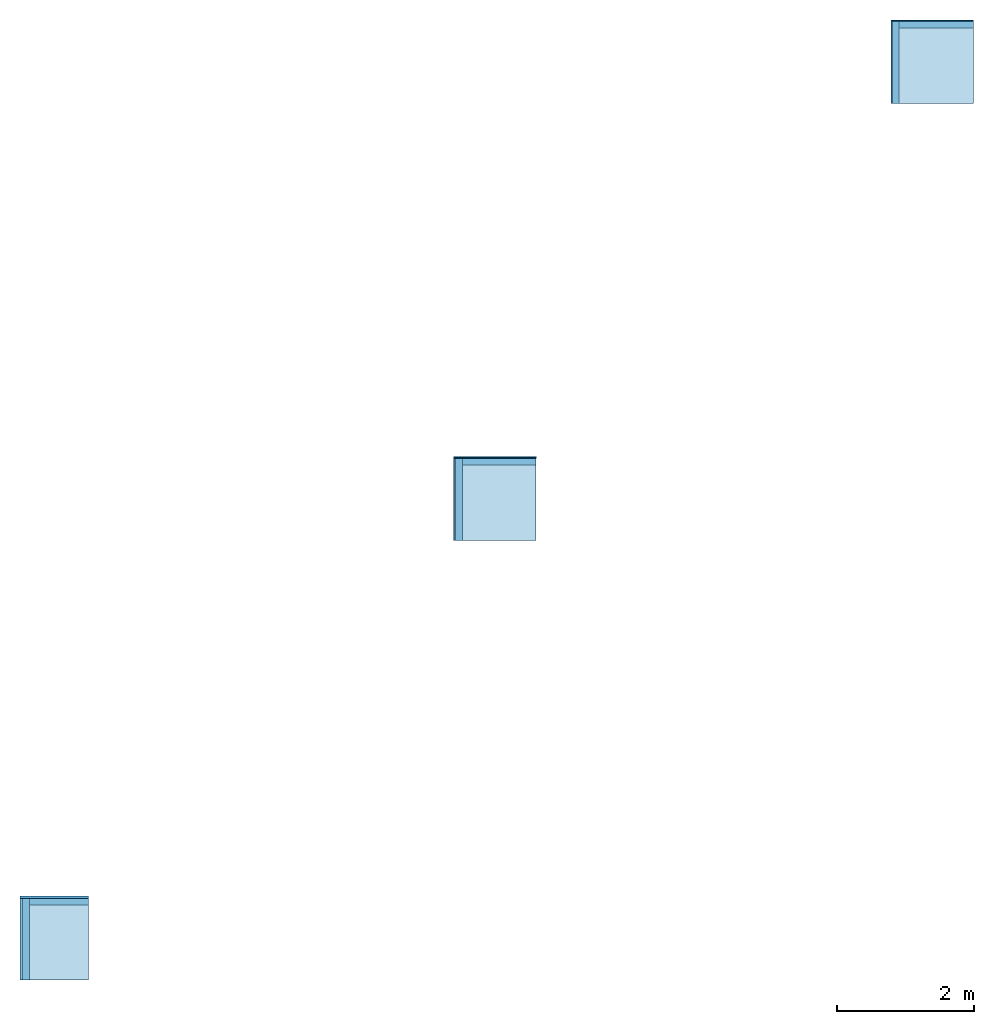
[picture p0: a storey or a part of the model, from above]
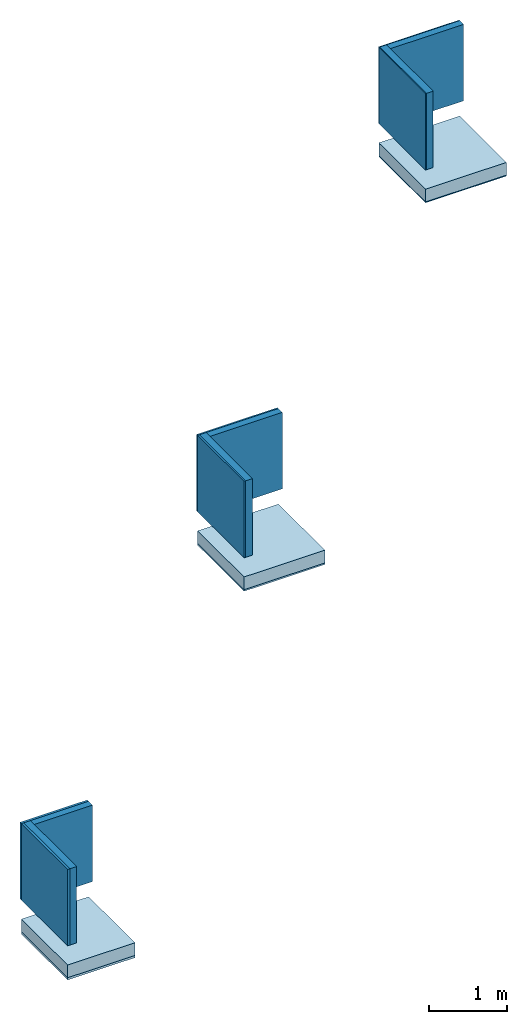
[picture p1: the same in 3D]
Properties of the parts of a building model (IFC2X3)

# File
Description: ViewDefinition [CoordinationView, QuantityTakeOffAddOnView]
File name: 012345
Time: 2023-01-18T09:38:41
Written by: The EXPRESS Data Manager Version 5.02.0100.07 : 28 Aug 2013
Made in: 21.1.70.21 - Exporter 21.1.70.21 - Alternate UI 21.1.70.21
Comment: STEP Physical File produced by: The EXPRESS Data Manager Version 5.02.0100.07 : 28 Aug 2013 * Module: EDMstepFileFactory/EDMstandAlone * Creation date: Wed Jan 18 09:38:41 2023 * Host: BIM-LT03 * Database: C:\Users\DONNEE~1\AppData\Local\Temp\6dfd9f73-01cb-4fe2-bb7c-203e315a706e\4447c928-8483-4c6d-8fab-7a3299bfe652\ifc * Database version: 5507 * Database creation date: Wed Jan 18 09:38:40 2023 * Schema: IFC2X3 * Model: DataRepository.ifc * Model creation date: Wed Jan 18 09:38:41 2023 * Header model: DataRepository.ifc_HeaderModel * Header model creation date: Wed Jan 18 09:38:41 2023 * EDMuser: sdai-user * EDMgroup: sdai-group * License ID and type: 5605 : Permanent license. Expiry date: * EDMstepFileFactory options: 020000

# IfcProject, 012345
LongName: Cadix Project Naam; Phase: Cadix leeg V2.0

# IfcSite, Default
RefLatitude: 52, 3, 20, 225830; RefLongitude: 5, 6, 28, 692855; RefElevation: 0 mm
Pset_ProductRequirements - Category: Project Information

# IfcBuilding
Pset_BuildingCommon - NumberOfStoreys: 2
Pset_ProductRequirements - Category: Project Information

# IfcBuildingStorey: Level:niveau (2)
Pset_ProductRequirements - Category: Levels
Name | LongName = Pset_AirSideSystemInformation, Name = Pset_ProductRequirements, Name | Elevation (mm)
00 begane grond | 00 begane grond | -2.7707e-11
01 eerste verdieping | 01 eerste verdieping | 1200

# IfcCovering: Compound Ceiling:NLRS_45_CEI_Heraklith A2 afbouwpaneel 15x1200x600mm, Compound Ceiling:NLRS_45_CEI_Heraklith A2 afbouwpaneel 15x1200x600mm:888459
In: 01 eerste verdieping
Type - PredefinedType: CEILING
Type - Pset_CoveringCommon - Reference: Compound Ceiling:NLRS_45_CEI_Heraklith A2 afbouwpaneel 15x1200x600mm; TotalThickness: 15 mm
Type - Pset_ElementShading - Roughness: 304.8 mm
Type - Pset_ManufacturerTypeInformation - Manufacturer: Knauf Insulation B.V.
Type - Pset_ProductRequirements - Category: Ceilings
Type - Pset_QuantityTakeOff - Reference: Compound Ceiling:NLRS_45_CEI_Heraklith A2 afbouwpaneel 15x1200x600mm
Type - Pset_Ceiling_Schedule_LOD200 - Assembly Code: 45.0; Type Image: Raster image: Heraklith A2 Afbouwpaneel.jpg; Model: Heraklith® | A2 afbouwpaneel is een A2 houtwolcementpaneel; Manufacturer: Knauf Insulation B.V.; URL: www.heraklith.nl; Description: A2 afbouwpaneel - 15mm; phone: +31(0)162-421245; email: customerservice.nl@knaufinsulation.com; product URL: https://heraklith.nl/houtwol-producten/a2-afbouwpaneel; warmteweerstand: 0,15 (m2.K/W); NLRS_C_Code_Brandklasse: A2-s1,d0; brandweerstand: REI 60 mits verwerkt tegen massief beton conform classificatierapport nr 16210B / 16211B; geluidsabsorbtie: niet getest; DoP: W4302APCPR; NLRS_C_content_creator: Knauf Insulation; NLRS_C_content_versie: V1.0
Classification: 45.0 (Uniformat); Material: Heraklith A2 afbouwpaneel - Houtwollaag - 1200x600mm 15 mm
Pset_CoveringCommon - Finish: Heraklith A2 afbouwpaneel - Houtwollaag - 1200x600mm;
Pset_Ceiling_Schedule_LOD200 - Type: Compound Ceiling: NLRS_45_CEI_Heraklith A2 afbouwpaneel 15x1200x600mm
BaseQuantities - GrossCeilingArea: 1.44 m2

# IfcCovering: Compound Ceiling:NLRS_45_CEI_Heraklith A2 afbouwpaneel 25x1200x600mm, Compound Ceiling:NLRS_45_CEI_Heraklith A2 afbouwpaneel 25x1200x600mm:912503
In: 01 eerste verdieping
Type - PredefinedType: CEILING
Type - Pset_CoveringCommon - Reference: Compound Ceiling:NLRS_45_CEI_Heraklith A2 afbouwpaneel 25x1200x600mm; TotalThickness: 25 mm
Type - Pset_ElementShading - Roughness: 304.8 mm
Type - Pset_ManufacturerTypeInformation - Manufacturer: Knauf Insulation B.V.
Type - Pset_ProductRequirements - Category: Ceilings
Type - Pset_QuantityTakeOff - Reference: Compound Ceiling:NLRS_45_CEI_Heraklith A2 afbouwpaneel 25x1200x600mm
Type - Pset_Ceiling_Schedule_LOD200 - Assembly Code: 45.0; Type Image: Raster image: Heraklith A2 Afbouwpaneel.jpg; Model: Heraklith® | A2 afbouwpaneel is een A2 houtwolcementpaneel; Manufacturer: Knauf Insulation B.V.; URL: www.heraklith.nl; Description: A2 afbouwpaneel - 25mm; phone: +31(0)162-421245; email: customerservice.nl@knaufinsulation.com; product URL: https://heraklith.nl/houtwol-producten/a2-afbouwpaneel; warmteweerstand: 0,25 (m2.K/W); NLRS_C_Code_Brandklasse: A2-s1,d0; brandweerstand: REI 60 mits verwerkt tegen massief beton conform classificatierapport nr 16210B / 16211B; geluidsabsorbtie: max. 0,90; DoP: W4302APCPR; NLRS_C_content_creator: Knauf Insulation; NLRS_C_content_versie: V1.0
Classification: 45.0 (Uniformat); Material: Heraklith A2 afbouwpaneel - Houtwollaag - 1200x600mm 25 mm
Pset_CoveringCommon - Finish: Heraklith A2 afbouwpaneel - Houtwollaag - 1200x600mm;
Pset_Ceiling_Schedule_LOD200 - Type: Compound Ceiling: NLRS_45_CEI_Heraklith A2 afbouwpaneel 25x1200x600mm
BaseQuantities - GrossCeilingArea: 1.434 m2

# IfcCovering: Compound Ceiling:NLRS_45_CEI_Heraklith A2 afbouwpaneel 35x1000x600mm, Compound Ceiling:NLRS_45_CEI_Heraklith A2 afbouwpaneel 35x1000x600mm:914120
In: 01 eerste verdieping
Type - PredefinedType: CEILING
Type - Pset_CoveringCommon - Reference: Compound Ceiling:NLRS_45_CEI_Heraklith A2 afbouwpaneel 35x1000x600mm; TotalThickness: 35 mm
Type - Pset_ElementShading - Roughness: 304.8 mm
Type - Pset_ManufacturerTypeInformation - Manufacturer: Knauf Insulation B.V.
Type - Pset_ProductRequirements - Category: Ceilings
Type - Pset_QuantityTakeOff - Reference: Compound Ceiling:NLRS_45_CEI_Heraklith A2 afbouwpaneel 35x1000x600mm
Type - Pset_Ceiling_Schedule_LOD200 - Assembly Code: 45.0; Type Image: Raster image: Heraklith A2 Afbouwpaneel.jpg; Model: Heraklith® | A2 afbouwpaneel is een A2 houtwolcementpaneel; Manufacturer: Knauf Insulation B.V.; URL: www.heraklith.nl; Description: A2 afbouwpaneel - 35mm; phone: +31(0)162-421245; email: customerservice.nl@knaufinsulation.com; product URL: https://heraklith.nl/houtwol-producten/a2-afbouwpaneel; warmteweerstand: 0,40 (m2.K/W); NLRS_C_Code_Brandklasse: A2-s1,d0; brandweerstand: REI 60 mits verwerkt tegen massief beton conform classificatierapport nr 16210B / 16211B; geluidsabsorbtie: 0,40; DoP: W4302APCPR; NLRS_C_content_creator: Knauf Insulation; NLRS_C_content_versie: V1.0
Classification: 45.0 (Uniformat); Material: Heraklith A2 afbouwpaneel - Houtwollaag - 1000x600mm 35 mm
Pset_CoveringCommon - Finish: Heraklith A2 afbouwpaneel - Houtwollaag - 1000x600mm;
Pset_Ceiling_Schedule_LOD200 - Type: Compound Ceiling: NLRS_45_CEI_Heraklith A2 afbouwpaneel 35x1000x600mm
BaseQuantities - GrossCeilingArea: 1.19 m2

# IfcSlab: Floor:Generic 200mm (6)
Type - PredefinedType: FLOOR; Material: Concrete, Precast Panels 200 mm
Type - Pset_ElementShading - Roughness: 914.4 mm
Type - Pset_ProductRequirements - Category: Floors
Type - Pset_QuantityTakeOff - Reference: Floor:Generic 200mm
Type - Pset_ReinforcementBarPitchOfSlab - Reference: Floor:Generic 200mm
Type - Pset_SlabCommon - IsExternal: no; Reference: Floor:Generic 200mm; ThermalTransmittance: 5.23 kg/K/s3
Pset_QuantityTakeOff - sets with these values: 2
Pset_SlabCommon - LoadBearing: no; PitchAngle: 0 deg
BaseQuantities - Width: 200 mm
Name (Floor:Generic 200mm:...) | In | GrossArea (m2) | NetArea (m2) | GrossVolume (m3) | NetVolume (m3) | Perimeter (mm)
915309 | 00 begane grond | 1.44 | 3.84 | 288 | 0.288 | 4800
915454 | 00 begane grond | 1.434 | 3.826 | 286.8 | 0.2868 | 4790
915523 | 00 begane grond | 1.19 | 3.256 | 238 | 0.238 | 4380
916757 | 01 eerste verdieping | 1.44 | 3.84 | 288 | 0.288 | 4800
916812 | 01 eerste verdieping | 1.434 | 3.826 | 286.8 | 0.2868 | 4790
916986 | 01 eerste verdieping | 1.19 | 3.256 | 238 | 0.238 | 4380

# IfcSlab: Floor:NLRS_23_FL_Heraklith A2 afbouwpaneel 15x1200x600mm, Floor:NLRS_23_FL_Heraklith A2 afbouwpaneel 15x1200x600mm:889765
In: 00 begane grond
Type - PredefinedType: FLOOR; Material: Heraklith A2 afbouwpaneel - Houtwollaag - 1200x600mm 15 mm
Type - Pset_ElementShading - Roughness: 304.8 mm
Type - Pset_ManufacturerTypeInformation - Manufacturer: Knauf Insulation B.V.
Type - Pset_ProductRequirements - Category: Floors
Type - Pset_QuantityTakeOff - Reference: Floor:NLRS_23_FL_Heraklith A2 afbouwpaneel 15x1200x600mm
Type - Pset_ReinforcementBarPitchOfSlab - Description: A2 afbouwpaneel - 15mm; Reference: Floor:NLRS_23_FL_Heraklith A2 afbouwpaneel 15x1200x600mm
Type - Pset_SlabCommon - IsExternal: no; Reference: Floor:NLRS_23_FL_Heraklith A2 afbouwpaneel 15x1200x600mm; ThermalTransmittance: 56.6667 kg/K/s3
Type - Pset_Floor_Schedule_ LOD200 - Assembly Code: 23.0; Type Image: Raster image: Heraklith A2 Afbouwpaneel.jpg; Model: Heraklith® | A2 afbouwpaneel is een A2 houtwolcementpaneel; Manufacturer: Knauf Insulation B.V.; URL: www.heraklith.nl; Description: A2 afbouwpaneel - 15mm; phone: +31(0)162-421245; email: customerservice.nl@knaufinsulation.com; product URL: https://heraklith.nl/houtwol-producten/a2-afbouwpaneel; warmteweerstand: 0,15 (m2.K/W); NLRS_C_Code_Brandklasse: A2-s1,d0; brandweerstand: REI 60 mits verwerkt tegen massief beton conform classificatierapport nr 16210B / 16211B; geluidsabsorbtie: niet getest; DoP: W4302APCPR; NLRS_C_content_creator: Knauf Insulation; NLRS_C_content_versie: V1.0
Classification: 23.0 (Uniformat)
Pset_SlabCommon - LoadBearing: no; IsExternal: yes; PitchAngle: 0 deg
Pset_Floor_Schedule_ LOD200 - Type: Floor: NLRS_23_FL_Heraklith A2 afbouwpaneel 15x1200x600mm
BaseQuantities - GrossArea: 1.44 m2; NetArea: 2.952 m2; GrossVolume: 21.6 m3; NetVolume: 0.0216 m3; Perimeter: 4800 mm; Width: 15 mm

# IfcSlab: Floor:NLRS_23_FL_Heraklith A2 afbouwpaneel 25x1200x600mm, Floor:NLRS_23_FL_Heraklith A2 afbouwpaneel 25x1200x600mm:912512
In: 00 begane grond
Type - PredefinedType: FLOOR; Material: Heraklith A2 afbouwpaneel - Houtwollaag - 1200x600mm 25 mm
Type - Pset_ElementShading - Roughness: 304.8 mm
Type - Pset_ManufacturerTypeInformation - Manufacturer: Knauf Insulation B.V.
Type - Pset_ProductRequirements - Category: Floors
Type - Pset_QuantityTakeOff - Reference: Floor:NLRS_23_FL_Heraklith A2 afbouwpaneel 25x1200x600mm
Type - Pset_ReinforcementBarPitchOfSlab - Description: A2 afbouwpaneel - 25mm; Reference: Floor:NLRS_23_FL_Heraklith A2 afbouwpaneel 25x1200x600mm
Type - Pset_SlabCommon - IsExternal: no; Reference: Floor:NLRS_23_FL_Heraklith A2 afbouwpaneel 25x1200x600mm; ThermalTransmittance: 34 kg/K/s3
Type - Pset_Floor_Schedule_ LOD200 - Assembly Code: 23.0; Type Image: Raster image: Heraklith A2 Afbouwpaneel.jpg; Model: Heraklith® | A2 afbouwpaneel is een A2 houtwolcementpaneel; Manufacturer: Knauf Insulation B.V.; URL: www.heraklith.nl; Description: A2 afbouwpaneel - 25mm; phone: +31(0)162-421245; email: customerservice.nl@knaufinsulation.com; product URL: https://heraklith.nl/houtwol-producten/a2-afbouwpaneel; warmteweerstand: 0,25 (m2.K/W); NLRS_C_Code_Brandklasse: A2-s1,d0; brandweerstand: REI 60 mits verwerkt tegen massief beton conform classificatierapport nr 16210B / 16211B; geluidsabsorbtie: max. 0,90; DoP: W4302APCPR; NLRS_C_content_creator: Knauf Insulation; NLRS_C_content_versie: V1.0
Classification: 23.0 (Uniformat)
Pset_SlabCommon - LoadBearing: no; IsExternal: yes; PitchAngle: 0 deg
Pset_Floor_Schedule_ LOD200 - Type: Floor: NLRS_23_FL_Heraklith A2 afbouwpaneel 25x1200x600mm
BaseQuantities - GrossArea: 1.434 m2; NetArea: 2.98775 m2; GrossVolume: 35.85 m3; NetVolume: 0.03585 m3; Perimeter: 4790 mm; Width: 25 mm

# IfcSlab: Floor:NLRS_23_FL_Heraklith A2 afbouwpaneel 35x1000x600mm, Floor:NLRS_23_FL_Heraklith A2 afbouwpaneel 35x1000x600mm:914109
In: 00 begane grond
Type - PredefinedType: FLOOR; Material: Heraklith A2 afbouwpaneel - Houtwollaag - 1000x600mm 35 mm
Type - Pset_ElementShading - Roughness: 304.8 mm
Type - Pset_ManufacturerTypeInformation - Manufacturer: Knauf Insulation B.V.
Type - Pset_ProductRequirements - Category: Floors
Type - Pset_QuantityTakeOff - Reference: Floor:NLRS_23_FL_Heraklith A2 afbouwpaneel 35x1000x600mm
Type - Pset_ReinforcementBarPitchOfSlab - Description: A2 afbouwpaneel - 35mm; Reference: Floor:NLRS_23_FL_Heraklith A2 afbouwpaneel 35x1000x600mm
Type - Pset_SlabCommon - IsExternal: no; Reference: Floor:NLRS_23_FL_Heraklith A2 afbouwpaneel 35x1000x600mm; ThermalTransmittance: 24.2857 kg/K/s3
Type - Pset_Floor_Schedule_ LOD200 - Assembly Code: 23.0; Type Image: Raster image: Heraklith A2 Afbouwpaneel.jpg; Model: Heraklith® | A2 afbouwpaneel is een A2 houtwolcementpaneel; Manufacturer: Knauf Insulation B.V.; URL: www.heraklith.nl; Description: A2 afbouwpaneel - 35mm; phone: +31(0)162-421245; email: customerservice.nl@knaufinsulation.com; product URL: https://heraklith.nl/houtwol-producten/a2-afbouwpaneel; warmteweerstand: 0,40 (m2.K/W); NLRS_C_Code_Brandklasse: A2-s1,d0; brandweerstand: REI 60 mits verwerkt tegen massief beton conform classificatierapport nr 16210B / 16211B; geluidsabsorbtie: 0,40; DoP: W4302APCPR; NLRS_C_content_creator: Knauf Insulation; NLRS_C_content_versie: V1.0
Classification: 23.0 (Uniformat)
Pset_SlabCommon - LoadBearing: no; IsExternal: yes; PitchAngle: 0 deg
Pset_Floor_Schedule_ LOD200 - Type: Floor: NLRS_23_FL_Heraklith A2 afbouwpaneel 35x1000x600mm
BaseQuantities - GrossArea: 1.19 m2; NetArea: 2.5333 m2; GrossVolume: 41.65 m3; NetVolume: 0.04165 m3; Perimeter: 4380 mm; Width: 35 mm

# IfcWallStandardCase: Basic Wall:Generic_100mm (6)
In: 00 begane grond
Type - PredefinedType: STANDARD; Material: Concrete, Precast Panels 100 mm
Type - Pset_ElementShading - Roughness: 914.4 mm
Type - Pset_ProductRequirements - Category: Walls
Type - Pset_QuantityTakeOff - Reference: Basic Wall:Generic_100mm
Type - Pset_ReinforcementBarPitchOfWall - Reference: Basic Wall:Generic_100mm
Type - Pset_WallCommon - IsExternal: no; Reference: Basic Wall:Generic_100mm; ThermalTransmittance: 10.46 kg/K/s3
BaseQuantities - Height: 1200 mm; Width: 100 mm
Pset_QuantityTakeOff - sets with these values: 2
Pset_WallCommon - ExtendToStructure: no; LoadBearing: no; IsExternal: yes
Name (Basic Wall:Generic_100mm:...) | Length (mm) | GrossFootprintArea (m2) | NetVolume (m3) | NetSideArea (m2)
915746 | 1200 | 0.12 | 144000000 | 1440000
915832 | 1085 | 0.1085 | 130200000 | 1302000
916208 | 1195 | 0.1195 | 143400000 | 1434000
916288 | 1075 | 0.1075 | 129000000 | 1290000
916512 | 1190 | 0.119 | 142800000 | 1428000
916584 | 865 | 0.0865 | 103800000 | 1038000

# IfcWallStandardCase: Basic Wall:NLRS_41_WA_Heraklith A2 afbouwpaneel 15x1200x600mm, Basic Wall:NLRS_41_WA_Heraklith A2 afbouwpaneel 15x1200x600mm:888766
In: 00 begane grond
Type - PredefinedType: STANDARD; Material: Heraklith A2 afbouwpaneel - Houtwollaag - 1200x600mm 15 mm
Type - Pset_ElementShading - Roughness: 304.8 mm
Type - Pset_ManufacturerTypeInformation - Manufacturer: Knauf Insulation B.V.
Type - Pset_ProductRequirements - Category: Walls
Type - Pset_QuantityTakeOff - Reference: Basic Wall:NLRS_41_WA_Heraklith A2 afbouwpaneel 15x1200x600mm
Type - Pset_ReinforcementBarPitchOfWall - Description: A2 afbouwpaneel - 15mm; Reference: Basic Wall:NLRS_41_WA_Heraklith A2 afbouwpaneel 15x1200x600mm
Type - Pset_WallCommon - Reference: Basic Wall:NLRS_41_WA_Heraklith A2 afbouwpaneel 15x1200x600mm; ThermalTransmittance: 56.6667 kg/K/s3; IsExternal: no
Type - Pset_Wall_Schedule_LOD200 - Assembly Code: 41.10; Type Image: Raster image: Heraklith A2 Afbouwpaneel.jpg; Model: Heraklith® | A2 afbouwpaneel is een A2 houtwolcementpaneel; Manufacturer: Knauf Insulation B.V.; URL: www.heraklith.nl; Description: A2 afbouwpaneel - 15mm; phone: +31(0)162-421245; email: customerservice.nl@knaufinsulation.com; product URL: https://heraklith.nl/houtwol-producten/a2-afbouwpaneel; warmteweerstand: 0,15 (m2.K/W); NLRS_C_Code_Brandklasse: A2-s1,d0; brandweerstand: REI 60 mits verwerkt tegen massief beton conform classificatierapport nr 16210B / 16211B; geluidsabsorbtie: niet getest; DoP: W4302APCPR; NLRS_C_content_creator: Knauf Insulation; NLRS_C_content_versie: V1.0
Classification: 41.10 (Uniformat)
BaseQuantities - Height: 1200 mm; Length: 1200 mm; Width: 15 mm; GrossFootprintArea: 0.018 m2; NetVolume: 21600000 m3; NetSideArea: 1440000 m2
Pset_WallCommon - ExtendToStructure: no; LoadBearing: no
Pset_Wall_Schedule_LOD200 - Type: Basic Wall: NLRS_41_WA_Heraklith A2 afbouwpaneel 15x1200x600mm

# IfcWallStandardCase: Basic Wall:NLRS_41_WA_Heraklith A2 afbouwpaneel 25x1200x600mm, Basic Wall:NLRS_41_WA_Heraklith A2 afbouwpaneel 25x1200x600mm:912508
In: 00 begane grond
Type - PredefinedType: STANDARD; Material: Heraklith A2 afbouwpaneel - Houtwollaag - 1200x600mm 25 mm
Type - Pset_ElementShading - Roughness: 304.8 mm
Type - Pset_ManufacturerTypeInformation - Manufacturer: Knauf Insulation B.V.
Type - Pset_ProductRequirements - Category: Walls
Type - Pset_QuantityTakeOff - Reference: Basic Wall:NLRS_41_WA_Heraklith A2 afbouwpaneel 25x1200x600mm
Type - Pset_ReinforcementBarPitchOfWall - Description: A2 afbouwpaneel - 25mm; Reference: Basic Wall:NLRS_41_WA_Heraklith A2 afbouwpaneel 25x1200x600mm
Type - Pset_WallCommon - IsExternal: no; Reference: Basic Wall:NLRS_41_WA_Heraklith A2 afbouwpaneel 25x1200x600mm; ThermalTransmittance: 34 kg/K/s3
Type - Pset_Wall_Schedule_LOD200 - Assembly Code: 41.10; Type Image: Raster image: Heraklith A2 Afbouwpaneel.jpg; Model: Heraklith® | A2 afbouwpaneel is een A2 houtwolcementpaneel; Manufacturer: Knauf Insulation B.V.; URL: www.heraklith.nl; Description: A2 afbouwpaneel - 25mm; phone: +31(0)162-421245; email: customerservice.nl@knaufinsulation.com; product URL: https://heraklith.nl/houtwol-producten/a2-afbouwpaneel; warmteweerstand: 0,25 (m2.K/W) v; NLRS_C_Code_Brandklasse: A2-s1,d0; brandweerstand: REI 60 mits verwerkt tegen massief beton conform classificatierapport nr 16210B / 16211B; geluidsabsorbtie: max. 0,90; DoP: W4302APCPR; NLRS_C_content_creator: Knauf Insulation; NLRS_C_content_versie: V1.0
Classification: 41.10 (Uniformat)
BaseQuantities - Height: 1200 mm; Length: 1200 mm; Width: 25 mm; GrossFootprintArea: 0.03 m2; NetVolume: 36000000 m3; NetSideArea: 1440000 m2
Pset_WallCommon - ExtendToStructure: no; LoadBearing: no; IsExternal: yes
Pset_Wall_Schedule_LOD200 - Type: Basic Wall: NLRS_41_WA_Heraklith A2 afbouwpaneel 25x1200x600mm

# IfcWallStandardCase: Basic Wall:NLRS_41_WA_Heraklith A2 afbouwpaneel 35x1000x600mm, Basic Wall:NLRS_41_WA_Heraklith A2 afbouwpaneel 35x1000x600mm:914281
In: 00 begane grond
Type - PredefinedType: STANDARD; Material: Heraklith A2 afbouwpaneel - Houtwollaag - 1000x600mm 35 mm
Type - Pset_ElementShading - Roughness: 304.8 mm
Type - Pset_ManufacturerTypeInformation - Manufacturer: Knauf Insulation B.V.
Type - Pset_ProductRequirements - Category: Walls
Type - Pset_QuantityTakeOff - Reference: Basic Wall:NLRS_41_WA_Heraklith A2 afbouwpaneel 35x1000x600mm
Type - Pset_ReinforcementBarPitchOfWall - Description: A2 afbouwpaneel - 35mm; Reference: Basic Wall:NLRS_41_WA_Heraklith A2 afbouwpaneel 35x1000x600mm
Type - Pset_WallCommon - IsExternal: no; Reference: Basic Wall:NLRS_41_WA_Heraklith A2 afbouwpaneel 35x1000x600mm; ThermalTransmittance: 24.2857 kg/K/s3
Type - Pset_Wall_Schedule_LOD200 - Assembly Code: 41.10; Type Image: Raster image: Heraklith A2 Afbouwpaneel.jpg; Model: Heraklith® | A2 afbouwpaneel is een A2 houtwolcementpaneel; Manufacturer: Knauf Insulation B.V.; URL: www.heraklith.nl; Description: A2 afbouwpaneel - 35mm; phone: +31(0)162-421245; email: customerservice.nl@knaufinsulation.com; product URL: https://heraklith.nl/houtwol-producten/a2-afbouwpaneel; warmteweerstand: 0,40 (m2.K/W); NLRS_C_Code_Brandklasse: A2-s1,d0; brandweerstand: REI 60 mits verwerkt tegen massief beton conform classificatierapport nr 16210B / 16211B; geluidsabsorbtie: 0,40; DoP: W4302APCPR; NLRS_C_content_creator: Knauf Insulation; NLRS_C_content_versie: V1.0
Classification: 41.10 (Uniformat)
BaseQuantities - Height: 1200 mm; Length: 1000 mm; Width: 35 mm; GrossFootprintArea: 0.035 m2; NetVolume: 42000000 m3; NetSideArea: 1200000 m2
Pset_WallCommon - ExtendToStructure: no; LoadBearing: no; IsExternal: yes
Pset_Wall_Schedule_LOD200 - Type: Basic Wall: NLRS_41_WA_Heraklith A2 afbouwpaneel 35x1000x600mm

# IfcWallStandardCase: Basic Wall:NLRS_42_WA_Heraklith A2 afbouwpaneel 15x1200x600mm, Basic Wall:NLRS_42_WA_Heraklith A2 afbouwpaneel 15x1200x600mm:890945
In: 00 begane grond
Type - PredefinedType: STANDARD; Material: Heraklith A2 afbouwpaneel - Houtwollaag - 1200x600mm 15 mm
Type - Pset_ElementShading - Roughness: 304.8 mm
Type - Pset_ManufacturerTypeInformation - Manufacturer: Knauf Insulation B.V.
Type - Pset_ProductRequirements - Category: Walls
Type - Pset_QuantityTakeOff - Reference: Basic Wall:NLRS_42_WA_Heraklith A2 afbouwpaneel 15x1200x600mm
Type - Pset_ReinforcementBarPitchOfWall - Description: A2 afbouwpaneel - 15mm; Reference: Basic Wall:NLRS_42_WA_Heraklith A2 afbouwpaneel 15x1200x600mm
Type - Pset_WallCommon - IsExternal: no; Reference: Basic Wall:NLRS_42_WA_Heraklith A2 afbouwpaneel 15x1200x600mm; ThermalTransmittance: 56.6667 kg/K/s3
Type - Pset_Wall_Schedule_LOD200 - Assembly Code: 42.10; Type Image: Raster image: Heraklith A2 Afbouwpaneel.jpg; Model: Heraklith® | A2 afbouwpaneel is een A2 houtwolcementpaneel; Manufacturer: Knauf Insulation B.V.; URL: www.heraklith.nl; Description: A2 afbouwpaneel - 15mm; phone: +31(0)162-421245; email: customerservice.nl@knaufinsulation.com; product URL: https://heraklith.nl/houtwol-producten/a2-afbouwpaneel; warmteweerstand: 0,15 (m2.K/W); NLRS_C_Code_Brandklasse: A2-s1,d0; brandweerstand: REI 60 mits verwerkt tegen massief beton conform classificatierapport nr 16210B / 16211B; geluidsabsorbtie: niet getest; DoP: W4302APCPR; NLRS_C_content_creator: Knauf Insulation; NLRS_C_content_versie: V1.0
Classification: 42.10 (Uniformat)
BaseQuantities - Height: 1200 mm; Length: 1200 mm; Width: 15 mm; GrossFootprintArea: 0.018 m2; NetVolume: 21600000 m3; NetSideArea: 1440000 m2
Pset_WallCommon - ExtendToStructure: no; LoadBearing: no
Pset_Wall_Schedule_LOD200 - Type: Basic Wall: NLRS_42_WA_Heraklith A2 afbouwpaneel 15x1200x600mm

# IfcWallStandardCase: Basic Wall:NLRS_42_WA_Heraklith A2 afbouwpaneel 25x1200x600mm, Basic Wall:NLRS_42_WA_Heraklith A2 afbouwpaneel 25x1200x600mm:912518
In: 00 begane grond
Type - PredefinedType: STANDARD; Material: Heraklith A2 afbouwpaneel - Houtwollaag - 1200x600mm 25 mm
Type - Pset_ElementShading - Roughness: 304.8 mm
Type - Pset_ManufacturerTypeInformation - Manufacturer: Knauf Insulation B.V.
Type - Pset_ProductRequirements - Category: Walls
Type - Pset_QuantityTakeOff - Reference: Basic Wall:NLRS_42_WA_Heraklith A2 afbouwpaneel 25x1200x600mm
Type - Pset_ReinforcementBarPitchOfWall - Description: A2 afbouwpaneel - 25mm; Reference: Basic Wall:NLRS_42_WA_Heraklith A2 afbouwpaneel 25x1200x600mm
Type - Pset_WallCommon - IsExternal: no; Reference: Basic Wall:NLRS_42_WA_Heraklith A2 afbouwpaneel 25x1200x600mm; ThermalTransmittance: 34 kg/K/s3
Type - Pset_Wall_Schedule_LOD200 - Assembly Code: 42.10; Type Image: Raster image: Heraklith A2 Afbouwpaneel.jpg; Model: Heraklith® | A2 afbouwpaneel is een A2 houtwolcementpaneel; Manufacturer: Knauf Insulation B.V.; URL: www.heraklith.nl; Description: A2 afbouwpaneel - 25mm; phone: +31(0)162-421245; email: customerservice.nl@knaufinsulation.com; product URL: https://heraklith.nl/houtwol-producten/a2-afbouwpaneel; warmteweerstand: 0,25 (m2.K/W); NLRS_C_Code_Brandklasse: A2-s1,d0; brandweerstand: REI 60 mits verwerkt tegen massief beton conform classificatierapport nr 16210B / 16211B; geluidsabsorbtie: max. 0,90; DoP: W4302APCPR; NLRS_C_content_creator: Knauf Insulation; NLRS_C_content_versie: V1.0
Classification: 42.10 (Uniformat)
BaseQuantities - Height: 1200 mm; Length: 1195 mm; Width: 25 mm; GrossFootprintArea: 0.029875 m2; NetVolume: 35850000 m3; NetSideArea: 1434000 m2
Pset_WallCommon - ExtendToStructure: no; LoadBearing: no
Pset_Wall_Schedule_LOD200 - Type: Basic Wall: NLRS_42_WA_Heraklith A2 afbouwpaneel 25x1200x600mm

# IfcWallStandardCase: Basic Wall:NLRS_42_WA_Heraklith A2 afbouwpaneel 35x1000x600mm, Basic Wall:NLRS_42_WA_Heraklith A2 afbouwpaneel 35x1000x600mm:914116
In: 00 begane grond
Type - PredefinedType: STANDARD; Material: Heraklith A2 afbouwpaneel - Houtwollaag - 2000x600mm 35 mm
Type - Pset_ElementShading - Roughness: 304.8 mm
Type - Pset_ManufacturerTypeInformation - Manufacturer: Knauf Insulation B.V.
Type - Pset_ProductRequirements - Category: Walls
Type - Pset_QuantityTakeOff - Reference: Basic Wall:NLRS_42_WA_Heraklith A2 afbouwpaneel 35x1000x600mm
Type - Pset_ReinforcementBarPitchOfWall - Description: A2 afbouwpaneel - 35mm; Reference: Basic Wall:NLRS_42_WA_Heraklith A2 afbouwpaneel 35x1000x600mm
Type - Pset_WallCommon - IsExternal: no; Reference: Basic Wall:NLRS_42_WA_Heraklith A2 afbouwpaneel 35x1000x600mm; ThermalTransmittance: 24.2857 kg/K/s3
Type - Pset_Wall_Schedule_LOD200 - Assembly Code: 42.10; Type Image: Raster image: Heraklith A2 Afbouwpaneel.jpg; Model: Heraklith® | A2 afbouwpaneel is een A2 houtwolcementpaneel; Manufacturer: Knauf Insulation B.V.; URL: www.heraklith.nl; Description: A2 afbouwpaneel - 35mm; phone: +31(0)162-421245; email: customerservice.nl@knaufinsulation.com; product URL: https://heraklith.nl/houtwol-producten/a2-afbouwpaneel; warmteweerstand: 0,40 (m2.K/W); NLRS_C_Code_Brandklasse: A2-s1,d0; brandweerstand: REI 60 mits verwerkt tegen massief beton conform classificatierapport nr 16210B / 16211B; geluidsabsorbtie: 0,40; DoP: W4302APCPR; NLRS_C_content_creator: Knauf Insulation; NLRS_C_content_versie: V1.0
Classification: 42.10 (Uniformat)
BaseQuantities - Height: 1200 mm; Length: 1190 mm; Width: 35 mm; GrossFootprintArea: 0.04165 m2; NetVolume: 49980000 m3; NetSideArea: 1428000 m2
Pset_WallCommon - ExtendToStructure: no; LoadBearing: no
Pset_Wall_Schedule_LOD200 - Type: Basic Wall: NLRS_42_WA_Heraklith A2 afbouwpaneel 35x1000x600mm
